VERSION 5.8 ;
BUSBITCHARS "[]" ;
DIVIDERCHAR "/" ;
UNITS DATABASE MICRONS 1000 ; END UNITS
MANUFACTURINGGRID 0.005 ;
LAYER metal1 TYPE ROUTING ; DIRECTION HORIZONTAL ; PITCH 0.2 ; WIDTH 0.1 ; SPACING 0.1 ; END metal1
SITE core CLASS CORE ; SIZE 1 BY 1 ; SYMMETRY Y ; END core
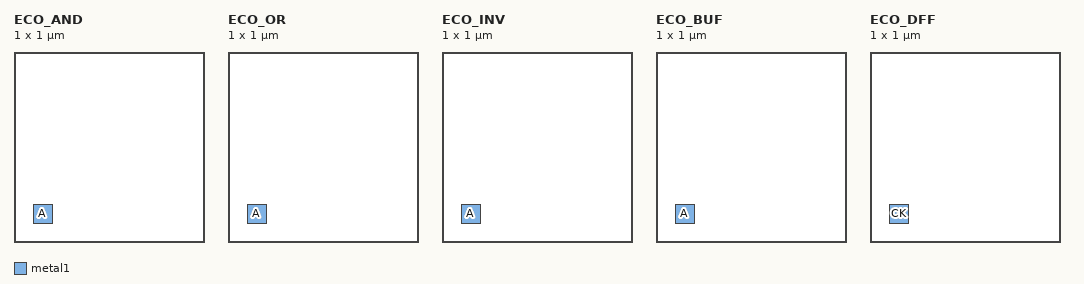
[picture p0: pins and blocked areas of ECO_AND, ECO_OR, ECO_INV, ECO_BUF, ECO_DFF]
MACRO ECO_AND
CLASS CORE ;
ORIGIN 0 0 ;
SIZE 1 BY 1 ;
SYMMETRY X Y ;
SITE core ;
PIN A
DIRECTION INPUT ;
USE SIGNAL ;
PORT LAYER metal1 ; RECT 0.1 0.1 0.2 0.2 ; END
END A
PIN B
DIRECTION INPUT ;
USE SIGNAL ;
PORT LAYER metal1 ; RECT 0.1 0.1 0.2 0.2 ; END
END B
PIN Y
DIRECTION OUTPUT ;
USE SIGNAL ;
PORT LAYER metal1 ; RECT 0.1 0.1 0.2 0.2 ; END
END Y
END ECO_AND
MACRO ECO_OR
CLASS CORE ;
ORIGIN 0 0 ;
SIZE 1 BY 1 ;
SYMMETRY X Y ;
SITE core ;
PIN A
DIRECTION INPUT ;
USE SIGNAL ;
PORT LAYER metal1 ; RECT 0.1 0.1 0.2 0.2 ; END
END A
PIN B
DIRECTION INPUT ;
USE SIGNAL ;
PORT LAYER metal1 ; RECT 0.1 0.1 0.2 0.2 ; END
END B
PIN Y
DIRECTION OUTPUT ;
USE SIGNAL ;
PORT LAYER metal1 ; RECT 0.1 0.1 0.2 0.2 ; END
END Y
END ECO_OR
MACRO ECO_INV
CLASS CORE ;
ORIGIN 0 0 ;
SIZE 1 BY 1 ;
SYMMETRY X Y ;
SITE core ;
PIN A
DIRECTION INPUT ;
USE SIGNAL ;
PORT LAYER metal1 ; RECT 0.1 0.1 0.2 0.2 ; END
END A
PIN Y
DIRECTION OUTPUT ;
USE SIGNAL ;
PORT LAYER metal1 ; RECT 0.1 0.1 0.2 0.2 ; END
END Y
END ECO_INV
MACRO ECO_BUF
CLASS CORE ;
ORIGIN 0 0 ;
SIZE 1 BY 1 ;
SYMMETRY X Y ;
SITE core ;
PIN A
DIRECTION INPUT ;
USE SIGNAL ;
PORT LAYER metal1 ; RECT 0.1 0.1 0.2 0.2 ; END
END A
PIN Y
DIRECTION OUTPUT ;
USE SIGNAL ;
PORT LAYER metal1 ; RECT 0.1 0.1 0.2 0.2 ; END
END Y
END ECO_BUF
MACRO ECO_DFF
CLASS CORE ;
ORIGIN 0 0 ;
SIZE 1 BY 1 ;
SYMMETRY X Y ;
SITE core ;
PIN CK
DIRECTION INPUT ;
USE CLOCK ;
PORT LAYER metal1 ; RECT 0.1 0.1 0.2 0.2 ; END
END CK
PIN RN
DIRECTION INPUT ;
USE SIGNAL ;
PORT LAYER metal1 ; RECT 0.1 0.1 0.2 0.2 ; END
END RN
PIN D
DIRECTION INPUT ;
USE SIGNAL ;
PORT LAYER metal1 ; RECT 0.1 0.1 0.2 0.2 ; END
END D
PIN Q
DIRECTION OUTPUT ;
USE SIGNAL ;
PORT LAYER metal1 ; RECT 0.1 0.1 0.2 0.2 ; END
END Q
END ECO_DFF
END LIBRARY
